VERSION 5.7 ;
  NOWIREEXTENSIONATPIN ON ;
  DIVIDERCHAR "/" ;
  BUSBITCHARS "[]" ;
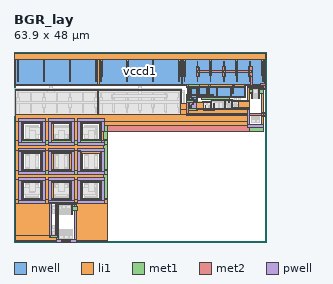
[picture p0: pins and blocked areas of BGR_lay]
MACRO BGR_lay
  CLASS BLOCK ;
  FOREIGN BGR_lay ;
  ORIGIN 0.000 0.000 ;
  SIZE 63.900 BY 48.000 ;
  PIN vccd1
    DIRECTION INOUT ;
    USE POWER ;
    PORT
      LAYER nwell ;
        RECT 0.135 39.565 63.645 46.405 ;
        RECT 43.500 38.980 58.500 39.565 ;
        RECT 43.950 36.430 58.500 38.980 ;
        RECT 43.950 36.415 51.505 36.430 ;
        RECT 43.950 35.550 46.410 36.415 ;
      LAYER li1 ;
        RECT 0.050 46.080 63.650 47.580 ;
        RECT 0.315 46.055 63.465 46.080 ;
        RECT 0.315 39.915 0.485 46.055 ;
        RECT 0.885 40.725 1.055 45.605 ;
        RECT 7.465 40.725 7.635 45.605 ;
        RECT 14.045 40.725 14.215 45.605 ;
        RECT 20.625 40.725 20.795 45.605 ;
        RECT 21.195 39.915 21.535 46.055 ;
        RECT 21.935 40.725 22.105 45.605 ;
        RECT 28.515 40.725 28.685 45.605 ;
        RECT 35.095 40.725 35.265 45.605 ;
        RECT 41.675 40.725 41.845 45.605 ;
        RECT 42.245 39.915 42.585 46.055 ;
        RECT 42.985 40.725 43.155 45.605 ;
        RECT 49.565 40.725 49.735 45.605 ;
        RECT 56.145 40.725 56.315 45.605 ;
        RECT 62.725 40.725 62.895 45.605 ;
        RECT 63.295 39.915 63.465 46.055 ;
        RECT 0.315 39.745 63.465 39.915 ;
        RECT 43.500 39.180 58.250 39.745 ;
        RECT 44.120 39.175 58.250 39.180 ;
        RECT 44.120 39.105 58.315 39.175 ;
        RECT 44.120 39.030 46.335 39.105 ;
        RECT 44.130 35.900 44.300 39.030 ;
        RECT 44.700 36.710 44.870 38.590 ;
        RECT 46.060 36.765 46.335 39.030 ;
        RECT 46.735 37.575 46.905 38.655 ;
        RECT 48.595 36.765 48.895 39.105 ;
        RECT 51.155 39.020 58.315 39.105 ;
        RECT 49.295 37.575 49.465 38.655 ;
        RECT 51.155 36.880 51.450 39.020 ;
        RECT 54.710 39.005 58.315 39.020 ;
        RECT 54.710 36.880 54.885 39.005 ;
        RECT 55.285 37.675 55.455 38.555 ;
        RECT 51.155 36.865 54.885 36.880 ;
        RECT 58.145 36.865 58.315 39.005 ;
        RECT 51.155 36.765 58.315 36.865 ;
        RECT 46.060 36.710 58.315 36.765 ;
        RECT 46.060 36.595 51.325 36.710 ;
        RECT 54.715 36.695 58.315 36.710 ;
        RECT 46.060 35.900 46.230 36.595 ;
        RECT 44.130 35.730 46.230 35.900 ;
      LAYER met1 ;
        RECT 0.000 46.080 63.700 47.580 ;
        RECT 0.800 41.880 1.200 46.080 ;
        RECT 7.350 41.930 7.750 46.080 ;
        RECT 13.900 41.930 14.300 46.080 ;
        RECT 0.855 40.665 1.085 41.880 ;
        RECT 7.435 40.665 7.665 41.930 ;
        RECT 14.015 40.665 14.245 41.930 ;
        RECT 20.550 41.830 20.950 46.080 ;
        RECT 20.595 40.665 20.825 41.830 ;
        RECT 21.850 41.780 22.250 46.080 ;
        RECT 28.400 41.830 28.800 46.080 ;
        RECT 34.950 41.880 35.350 46.080 ;
        RECT 41.550 41.930 41.950 46.080 ;
        RECT 42.850 41.930 43.250 46.080 ;
        RECT 49.450 41.980 49.850 46.080 ;
        RECT 56.050 41.980 56.450 46.080 ;
        RECT 62.600 41.980 63.000 46.080 ;
        RECT 21.905 40.665 22.135 41.780 ;
        RECT 28.485 40.665 28.715 41.830 ;
        RECT 35.065 40.665 35.295 41.880 ;
        RECT 41.645 40.665 41.875 41.930 ;
        RECT 42.955 40.665 43.185 41.930 ;
        RECT 49.535 40.665 49.765 41.980 ;
        RECT 56.115 40.665 56.345 41.980 ;
        RECT 62.695 40.665 62.925 41.980 ;
        RECT 43.970 39.130 46.950 39.680 ;
        RECT 49.150 39.380 49.600 39.730 ;
        RECT 55.150 39.430 55.600 39.830 ;
        RECT 43.970 38.830 46.420 39.130 ;
        RECT 44.670 38.650 44.870 38.830 ;
        RECT 44.670 36.650 44.900 38.650 ;
        RECT 46.700 37.530 46.950 39.130 ;
        RECT 49.250 37.530 49.500 39.380 ;
        RECT 55.250 37.630 55.500 39.430 ;
        RECT 55.255 37.615 55.485 37.630 ;
        RECT 46.705 37.515 46.935 37.530 ;
        RECT 49.265 37.515 49.495 37.530 ;
      LAYER met2 ;
        RECT 0.050 46.030 63.650 47.630 ;
        RECT 61.350 45.980 63.400 46.030 ;
    END
    PORT
      LAYER pwell ;
        RECT 58.970 38.850 63.080 39.360 ;
        RECT 44.005 33.265 46.365 35.455 ;
        RECT 1.200 30.365 7.900 31.130 ;
        RECT 1.200 25.195 1.965 30.365 ;
        RECT 7.135 25.195 7.900 30.365 ;
        RECT 1.200 24.430 7.900 25.195 ;
        RECT 8.640 30.365 15.340 31.130 ;
        RECT 8.640 25.195 9.405 30.365 ;
        RECT 14.575 25.195 15.340 30.365 ;
        RECT 8.640 24.430 15.340 25.195 ;
        RECT 16.080 30.365 22.780 31.130 ;
        RECT 16.080 25.195 16.845 30.365 ;
        RECT 22.015 25.195 22.780 30.365 ;
        RECT 58.970 29.610 59.580 38.850 ;
        RECT 62.470 29.610 63.080 38.850 ;
        RECT 58.970 28.900 63.080 29.610 ;
        RECT 16.080 24.430 22.780 25.195 ;
        RECT 1.200 22.915 7.900 23.680 ;
        RECT 1.200 17.745 1.965 22.915 ;
        RECT 7.135 17.745 7.900 22.915 ;
        RECT 1.200 16.980 7.900 17.745 ;
        RECT 8.650 22.915 15.350 23.680 ;
        RECT 8.650 17.745 9.415 22.915 ;
        RECT 14.585 17.745 15.350 22.915 ;
        RECT 8.650 16.980 15.350 17.745 ;
        RECT 16.100 22.965 22.800 23.730 ;
        RECT 16.100 17.795 16.865 22.965 ;
        RECT 22.035 17.795 22.800 22.965 ;
        RECT 16.100 17.030 22.800 17.795 ;
        RECT 1.200 15.565 7.900 16.330 ;
        RECT 1.200 10.395 1.965 15.565 ;
        RECT 7.135 10.395 7.900 15.565 ;
        RECT 1.200 9.630 7.900 10.395 ;
        RECT 8.640 15.565 15.340 16.330 ;
        RECT 8.640 10.395 9.405 15.565 ;
        RECT 14.575 10.395 15.340 15.565 ;
        RECT 8.640 10.060 15.340 10.395 ;
        RECT 16.080 15.565 22.780 16.330 ;
        RECT 16.080 10.395 16.845 15.565 ;
        RECT 22.015 10.395 22.780 15.565 ;
        RECT 8.640 9.630 15.780 10.060 ;
        RECT 16.080 9.630 22.780 10.395 ;
        RECT 9.050 9.620 15.780 9.630 ;
        RECT 9.050 1.560 9.480 9.620 ;
        RECT 10.530 9.600 15.780 9.620 ;
        RECT 10.530 1.560 11.130 9.600 ;
        RECT 9.050 1.130 11.130 1.560 ;
        RECT 10.670 0.560 11.130 1.130 ;
        RECT 15.320 0.560 15.780 9.600 ;
        RECT 10.670 0.000 15.780 0.560 ;
      LAYER li1 ;
        RECT 59.100 38.980 62.950 39.230 ;
        RECT 0.315 38.355 42.265 38.525 ;
        RECT 0.315 32.265 0.485 38.355 ;
        RECT 21.195 32.265 21.385 38.355 ;
        RECT 42.095 35.030 42.265 38.355 ;
        RECT 53.315 35.890 55.215 35.925 ;
        RECT 49.830 35.755 55.215 35.890 ;
        RECT 49.830 35.720 53.485 35.755 ;
        RECT 49.830 35.390 50.000 35.720 ;
        RECT 47.730 35.330 50.000 35.390 ;
        RECT 46.200 35.325 50.000 35.330 ;
        RECT 44.135 35.220 50.000 35.325 ;
        RECT 44.135 35.155 47.900 35.220 ;
        RECT 44.135 35.030 44.305 35.155 ;
        RECT 42.095 33.580 44.305 35.030 ;
        RECT 44.705 34.015 44.875 34.395 ;
        RECT 46.065 33.630 47.900 35.155 ;
        RECT 48.300 34.080 48.470 34.460 ;
        RECT 49.660 33.630 50.000 35.220 ;
        RECT 50.400 34.080 50.570 34.960 ;
        RECT 53.260 33.665 53.485 35.720 ;
        RECT 55.045 35.725 55.215 35.755 ;
        RECT 59.100 35.730 59.450 38.980 ;
        RECT 61.750 36.310 62.100 38.470 ;
        RECT 56.800 35.725 59.450 35.730 ;
        RECT 55.045 35.555 59.450 35.725 ;
        RECT 55.045 33.965 55.235 35.555 ;
        RECT 56.645 33.965 59.450 35.555 ;
        RECT 55.045 33.665 59.450 33.965 ;
        RECT 53.260 33.630 59.450 33.665 ;
        RECT 46.065 33.580 59.450 33.630 ;
        RECT 42.095 32.265 59.450 33.580 ;
        RECT 0.315 32.130 59.450 32.265 ;
        RECT 0.300 30.505 59.450 32.130 ;
        RECT 0.300 25.680 1.825 30.505 ;
        RECT 2.145 29.825 6.955 30.185 ;
        RECT 2.145 25.735 2.505 29.825 ;
        RECT 6.595 25.735 6.955 29.825 ;
        RECT 2.145 25.680 6.955 25.735 ;
        RECT 7.275 25.680 9.265 30.505 ;
        RECT 9.585 29.825 14.395 30.185 ;
        RECT 9.585 25.735 9.945 29.825 ;
        RECT 14.035 25.735 14.395 29.825 ;
        RECT 9.585 25.680 14.395 25.735 ;
        RECT 14.715 25.680 16.705 30.505 ;
        RECT 17.025 29.825 21.835 30.185 ;
        RECT 17.025 25.735 17.385 29.825 ;
        RECT 21.475 25.735 21.835 29.825 ;
        RECT 17.025 25.680 21.835 25.735 ;
        RECT 22.155 29.480 59.450 30.505 ;
        RECT 62.600 29.480 62.950 38.980 ;
        RECT 22.155 27.980 62.950 29.480 ;
        RECT 22.155 25.680 23.600 27.980 ;
        RECT 0.300 23.105 23.600 25.680 ;
        RECT 0.300 23.055 16.725 23.105 ;
        RECT 0.300 18.080 1.825 23.055 ;
        RECT 2.145 22.375 6.955 22.735 ;
        RECT 2.145 18.285 2.505 22.375 ;
        RECT 6.595 18.285 6.955 22.375 ;
        RECT 2.145 18.080 6.955 18.285 ;
        RECT 7.275 18.080 9.275 23.055 ;
        RECT 9.595 22.375 14.405 22.735 ;
        RECT 9.595 18.285 9.955 22.375 ;
        RECT 14.045 18.285 14.405 22.375 ;
        RECT 9.595 18.080 14.405 18.285 ;
        RECT 14.725 18.080 16.725 23.055 ;
        RECT 17.045 22.425 21.855 22.785 ;
        RECT 17.045 18.335 17.405 22.425 ;
        RECT 21.495 18.335 21.855 22.425 ;
        RECT 17.045 18.080 21.855 18.335 ;
        RECT 22.175 18.080 23.600 23.105 ;
        RECT 0.300 15.705 23.600 18.080 ;
        RECT 0.300 10.830 1.825 15.705 ;
        RECT 2.145 15.025 6.955 15.385 ;
        RECT 2.145 10.935 2.505 15.025 ;
        RECT 6.595 10.935 6.955 15.025 ;
        RECT 2.145 10.830 6.955 10.935 ;
        RECT 7.275 10.830 9.265 15.705 ;
        RECT 9.585 15.025 14.395 15.385 ;
        RECT 9.585 10.935 9.945 15.025 ;
        RECT 14.035 10.935 14.395 15.025 ;
        RECT 9.585 10.830 14.395 10.935 ;
        RECT 14.715 10.830 16.705 15.705 ;
        RECT 17.025 15.025 21.835 15.385 ;
        RECT 17.025 10.935 17.385 15.025 ;
        RECT 21.475 10.935 21.835 15.025 ;
        RECT 17.025 10.830 21.835 10.935 ;
        RECT 22.155 10.830 23.600 15.705 ;
        RECT 0.300 9.750 23.600 10.830 ;
        RECT 0.300 1.545 9.350 9.750 ;
        RECT 10.660 9.730 23.600 9.750 ;
        RECT 10.660 1.545 11.000 9.730 ;
        RECT 14.550 7.010 14.900 9.170 ;
        RECT 0.300 0.430 11.000 1.545 ;
        RECT 15.450 0.430 23.600 9.730 ;
        RECT 0.300 0.130 23.600 0.430 ;
      LAYER met1 ;
        RECT 61.800 38.430 62.050 38.440 ;
        RECT 61.750 37.580 62.950 38.430 ;
        RECT 61.800 36.335 62.050 37.580 ;
        RECT 50.370 34.980 50.600 35.020 ;
        RECT 44.675 34.430 44.905 34.455 ;
        RECT 44.670 33.955 44.905 34.430 ;
        RECT 48.270 34.020 48.500 34.520 ;
        RECT 44.670 33.680 44.870 33.955 ;
        RECT 44.070 33.130 46.370 33.680 ;
        RECT 48.300 33.630 48.450 34.020 ;
        RECT 50.350 33.630 50.600 34.980 ;
        RECT 47.750 33.130 50.600 33.630 ;
        RECT 22.650 27.980 62.950 29.480 ;
        RECT 22.650 25.880 23.600 27.980 ;
        RECT 1.350 24.580 23.600 25.880 ;
        RECT 22.650 18.380 23.600 24.580 ;
        RECT 1.350 17.080 23.600 18.380 ;
        RECT 22.650 11.030 23.600 17.080 ;
        RECT 1.350 9.730 23.600 11.030 ;
        RECT 14.600 8.880 14.850 9.140 ;
        RECT 14.600 7.930 16.050 8.880 ;
        RECT 14.600 7.035 14.850 7.930 ;
        RECT 9.165 1.245 10.865 1.545 ;
        RECT 12.050 0.130 14.300 0.430 ;
      LAYER met2 ;
        RECT 23.600 27.930 59.450 29.530 ;
    END
    PORT
      LAYER li1 ;
        RECT 46.275 40.725 46.445 45.605 ;
        RECT 52.855 40.725 53.025 45.605 ;
        RECT 59.435 40.725 59.605 45.605 ;
        RECT 59.950 36.320 60.300 38.480 ;
      LAYER met1 ;
        RECT 46.245 44.180 46.475 45.665 ;
        RECT 52.825 44.230 53.055 45.665 ;
        RECT 59.405 44.380 59.635 45.665 ;
        RECT 46.050 41.780 46.750 44.180 ;
        RECT 52.650 41.830 53.350 44.230 ;
        RECT 59.200 41.980 59.900 44.380 ;
        RECT 46.245 40.665 46.475 41.780 ;
        RECT 52.825 40.665 53.055 41.830 ;
        RECT 59.405 40.665 59.635 41.980 ;
        RECT 59.600 37.680 60.350 38.630 ;
        RECT 60.000 36.345 60.250 37.680 ;
      LAYER met2 ;
        RECT 46.100 43.330 46.700 44.230 ;
        RECT 52.700 43.330 53.300 44.280 ;
        RECT 59.250 43.330 60.300 44.430 ;
        RECT 46.100 42.730 60.300 43.330 ;
        RECT 46.100 41.730 46.700 42.730 ;
        RECT 52.700 41.780 53.300 42.730 ;
        RECT 59.250 41.930 60.300 42.730 ;
        RECT 59.650 39.630 60.300 41.930 ;
        RECT 62.150 39.630 63.650 39.980 ;
        RECT 59.650 38.780 63.650 39.630 ;
        RECT 59.650 37.630 60.300 38.780 ;
        RECT 62.150 38.480 63.650 38.780 ;
    END
    PORT
      LAYER li1 ;
        RECT 47.045 37.110 47.885 37.280 ;
        RECT 49.605 37.110 50.445 37.280 ;
        RECT 45.010 36.245 45.350 36.415 ;
        RECT 54.100 35.245 54.430 35.415 ;
        RECT 45.015 34.645 45.355 34.815 ;
      LAYER met1 ;
        RECT 46.900 36.980 48.000 37.330 ;
        RECT 49.500 37.310 50.350 37.330 ;
        RECT 49.500 37.080 50.505 37.310 ;
        RECT 49.500 37.030 50.350 37.080 ;
        RECT 44.950 36.215 45.410 36.445 ;
        RECT 47.300 36.380 47.550 36.980 ;
        RECT 45.020 35.630 45.370 36.215 ;
        RECT 47.300 36.080 54.450 36.380 ;
        RECT 43.550 35.230 45.370 35.630 ;
        RECT 54.100 35.230 54.450 36.080 ;
        RECT 45.020 34.845 45.370 35.230 ;
        RECT 54.120 35.215 54.410 35.230 ;
        RECT 44.955 34.615 45.415 34.845 ;
      LAYER met2 ;
        RECT 46.950 37.330 47.950 37.380 ;
        RECT 49.550 37.330 50.300 37.380 ;
        RECT 43.600 37.130 50.300 37.330 ;
        RECT 43.600 35.680 43.950 37.130 ;
        RECT 46.950 36.930 47.950 37.130 ;
        RECT 49.550 36.980 50.300 37.130 ;
        RECT 43.600 32.430 44.000 35.680 ;
        RECT 62.600 32.430 63.600 32.780 ;
        RECT 43.600 32.030 63.600 32.430 ;
        RECT 62.600 31.780 63.600 32.030 ;
    END
  END vccd1
  OBS
      LAYER pwell ;
        RECT 0.185 31.965 42.395 38.655 ;
        RECT 53.185 36.020 55.345 36.055 ;
        RECT 49.700 35.855 55.345 36.020 ;
        RECT 49.700 35.520 56.945 35.855 ;
        RECT 47.600 33.665 56.945 35.520 ;
        RECT 47.600 33.365 55.345 33.665 ;
        RECT 47.600 33.330 53.560 33.365 ;
        RECT 49.720 33.000 50.730 33.330 ;
      LAYER li1 ;
        RECT 4.175 40.725 4.345 45.605 ;
        RECT 10.755 40.725 10.925 45.605 ;
        RECT 17.335 40.725 17.505 45.605 ;
        RECT 25.225 40.725 25.395 45.605 ;
        RECT 31.805 40.725 31.975 45.605 ;
        RECT 38.385 40.725 38.555 45.605 ;
        RECT 1.195 40.260 4.035 40.430 ;
        RECT 4.485 40.260 7.325 40.430 ;
        RECT 7.775 40.260 10.615 40.430 ;
        RECT 11.065 40.260 13.905 40.430 ;
        RECT 14.355 40.260 17.195 40.430 ;
        RECT 17.645 40.260 20.485 40.430 ;
        RECT 22.245 40.260 25.085 40.430 ;
        RECT 25.535 40.260 28.375 40.430 ;
        RECT 28.825 40.260 31.665 40.430 ;
        RECT 32.115 40.260 34.955 40.430 ;
        RECT 35.405 40.260 38.245 40.430 ;
        RECT 38.695 40.260 41.535 40.430 ;
        RECT 43.295 40.260 46.135 40.430 ;
        RECT 46.585 40.260 49.425 40.430 ;
        RECT 49.875 40.260 52.715 40.430 ;
        RECT 53.165 40.260 56.005 40.430 ;
        RECT 56.455 40.260 59.295 40.430 ;
        RECT 59.745 40.260 62.585 40.430 ;
        RECT 1.195 37.845 4.035 38.015 ;
        RECT 4.485 37.845 7.325 38.015 ;
        RECT 7.775 37.845 10.615 38.015 ;
        RECT 11.065 37.845 13.905 38.015 ;
        RECT 14.355 37.845 17.195 38.015 ;
        RECT 17.645 37.845 20.485 38.015 ;
        RECT 22.095 37.845 24.935 38.015 ;
        RECT 25.385 37.845 28.225 38.015 ;
        RECT 28.675 37.845 31.515 38.015 ;
        RECT 31.965 37.845 34.805 38.015 ;
        RECT 35.255 37.845 38.095 38.015 ;
        RECT 38.545 37.845 41.385 38.015 ;
        RECT 0.885 32.715 1.055 37.595 ;
        RECT 4.175 32.715 4.345 37.595 ;
        RECT 7.465 32.715 7.635 37.595 ;
        RECT 10.755 32.715 10.925 37.595 ;
        RECT 14.045 32.715 14.215 37.595 ;
        RECT 17.335 32.715 17.505 37.595 ;
        RECT 20.625 32.715 20.795 37.595 ;
        RECT 21.785 32.715 21.955 37.595 ;
        RECT 25.075 32.715 25.245 37.595 ;
        RECT 28.365 32.715 28.535 37.595 ;
        RECT 31.655 32.715 31.825 37.595 ;
        RECT 34.945 32.715 35.115 37.595 ;
        RECT 38.235 32.715 38.405 37.595 ;
        RECT 41.525 32.715 41.695 37.595 ;
        RECT 45.490 36.710 45.660 38.590 ;
        RECT 48.025 37.575 48.195 38.655 ;
        RECT 50.585 37.575 50.755 38.655 ;
        RECT 51.850 37.690 52.020 38.570 ;
        RECT 54.140 37.690 54.310 38.570 ;
        RECT 57.575 37.675 57.745 38.555 ;
        RECT 52.160 37.225 54.000 37.395 ;
        RECT 55.595 37.210 57.435 37.380 ;
        RECT 60.550 36.310 60.900 38.470 ;
        RECT 61.150 36.310 61.500 38.470 ;
        RECT 50.710 35.210 52.550 35.380 ;
        RECT 55.775 35.045 56.105 35.215 ;
        RECT 48.610 34.710 48.950 34.880 ;
        RECT 45.495 34.015 45.665 34.395 ;
        RECT 49.090 34.080 49.260 34.460 ;
        RECT 52.690 34.080 52.860 34.960 ;
        RECT 53.885 34.115 54.055 34.995 ;
        RECT 54.475 34.115 54.645 34.995 ;
        RECT 55.635 34.415 55.805 34.795 ;
        RECT 56.075 34.415 56.245 34.795 ;
        RECT 59.950 30.140 60.300 32.300 ;
        RECT 60.550 30.130 60.900 32.290 ;
        RECT 61.150 30.130 61.500 32.290 ;
        RECT 61.750 30.130 62.100 32.290 ;
        RECT 2.815 26.045 6.285 29.515 ;
        RECT 10.255 26.045 13.725 29.515 ;
        RECT 17.695 26.045 21.165 29.515 ;
        RECT 2.815 18.595 6.285 22.065 ;
        RECT 10.265 18.595 13.735 22.065 ;
        RECT 17.715 18.645 21.185 22.115 ;
        RECT 2.815 11.245 6.285 14.715 ;
        RECT 10.255 11.245 13.725 14.715 ;
        RECT 17.695 11.245 21.165 14.715 ;
        RECT 9.830 7.110 10.180 9.270 ;
        RECT 11.550 7.010 11.900 9.170 ;
        RECT 12.150 7.010 12.500 9.170 ;
        RECT 12.750 7.010 13.100 9.170 ;
        RECT 13.350 7.010 13.700 9.170 ;
        RECT 13.950 7.010 14.300 9.170 ;
        RECT 9.830 1.910 10.180 4.070 ;
        RECT 11.550 0.930 11.900 3.090 ;
        RECT 12.150 0.930 12.500 3.090 ;
        RECT 12.750 0.930 13.100 3.090 ;
        RECT 13.350 0.930 13.700 3.090 ;
        RECT 13.950 0.930 14.300 3.090 ;
        RECT 14.550 0.930 14.900 3.090 ;
      LAYER met1 ;
        RECT 4.145 44.530 4.375 45.665 ;
        RECT 3.950 42.130 4.550 44.530 ;
        RECT 10.725 44.480 10.955 45.665 ;
        RECT 4.145 40.665 4.375 42.130 ;
        RECT 10.550 42.080 11.250 44.480 ;
        RECT 17.305 44.430 17.535 45.665 ;
        RECT 10.725 40.665 10.955 42.080 ;
        RECT 17.150 42.030 17.850 44.430 ;
        RECT 25.195 44.330 25.425 45.665 ;
        RECT 17.305 40.665 17.535 42.030 ;
        RECT 25.000 41.930 25.700 44.330 ;
        RECT 31.775 44.230 32.005 45.665 ;
        RECT 25.195 40.665 25.425 41.930 ;
        RECT 31.550 40.460 32.250 44.230 ;
        RECT 38.355 44.180 38.585 45.665 ;
        RECT 38.200 41.780 38.900 44.180 ;
        RECT 38.355 40.665 38.585 41.780 ;
        RECT 1.135 40.430 4.095 40.460 ;
        RECT 4.425 40.430 7.385 40.460 ;
        RECT 7.715 40.430 10.675 40.460 ;
        RECT 11.005 40.430 13.965 40.460 ;
        RECT 14.295 40.430 17.255 40.460 ;
        RECT 17.585 40.430 20.545 40.460 ;
        RECT 1.135 40.410 20.545 40.430 ;
        RECT 22.135 40.430 25.145 40.460 ;
        RECT 25.425 40.430 28.435 40.460 ;
        RECT 28.715 40.430 35.015 40.460 ;
        RECT 35.295 40.430 38.305 40.460 ;
        RECT 38.585 40.430 41.595 40.460 ;
        RECT 22.135 40.410 41.595 40.430 ;
        RECT 43.235 40.410 46.195 40.460 ;
        RECT 46.525 40.410 49.485 40.460 ;
        RECT 49.815 40.410 52.775 40.460 ;
        RECT 53.105 40.410 56.065 40.460 ;
        RECT 56.395 40.410 59.355 40.460 ;
        RECT 59.685 40.410 62.645 40.460 ;
        RECT 1.135 40.380 46.195 40.410 ;
        RECT 46.450 40.380 49.485 40.410 ;
        RECT 49.740 40.380 52.775 40.410 ;
        RECT 53.030 40.380 56.065 40.410 ;
        RECT 56.320 40.380 59.355 40.410 ;
        RECT 59.610 40.380 62.645 40.410 ;
        RECT 1.135 40.230 62.645 40.380 ;
        RECT 1.200 40.180 62.620 40.230 ;
        RECT 1.200 40.030 62.525 40.180 ;
        RECT 43.225 39.980 62.525 40.030 ;
        RECT 50.550 39.730 50.800 39.980 ;
        RECT 50.500 39.280 50.900 39.730 ;
        RECT 1.100 37.830 43.100 38.230 ;
        RECT 1.135 37.815 7.385 37.830 ;
        RECT 7.715 37.815 13.965 37.830 ;
        RECT 14.295 37.815 41.445 37.830 ;
        RECT 0.855 36.530 1.085 37.655 ;
        RECT 0.650 34.130 1.350 36.530 ;
        RECT 0.855 32.655 1.085 34.130 ;
        RECT 4.050 33.980 4.450 37.815 ;
        RECT 7.435 36.430 7.665 37.655 ;
        RECT 7.200 34.030 7.900 36.430 ;
        RECT 4.145 32.655 4.375 33.980 ;
        RECT 7.435 32.655 7.665 34.030 ;
        RECT 10.650 33.930 11.050 37.815 ;
        RECT 14.015 36.380 14.245 37.655 ;
        RECT 13.750 33.980 14.450 36.380 ;
        RECT 10.725 32.655 10.955 33.930 ;
        RECT 14.015 32.655 14.245 33.980 ;
        RECT 17.200 33.930 17.600 37.815 ;
        RECT 20.595 36.430 20.825 37.655 ;
        RECT 21.755 36.430 21.985 37.655 ;
        RECT 25.045 37.280 25.275 37.655 ;
        RECT 20.350 34.030 21.050 36.430 ;
        RECT 21.650 34.030 22.350 36.430 ;
        RECT 24.750 36.280 25.500 37.280 ;
        RECT 28.335 36.330 28.565 37.655 ;
        RECT 31.625 37.430 31.855 37.655 ;
        RECT 31.400 36.430 32.150 37.430 ;
        RECT 17.305 32.655 17.535 33.930 ;
        RECT 20.595 32.655 20.825 34.030 ;
        RECT 21.755 32.655 21.985 34.030 ;
        RECT 24.800 32.980 25.450 36.280 ;
        RECT 28.100 33.930 28.800 36.330 ;
        RECT 25.045 32.655 25.275 32.980 ;
        RECT 28.335 32.655 28.565 33.930 ;
        RECT 31.450 33.130 32.100 36.430 ;
        RECT 34.915 36.330 35.145 37.655 ;
        RECT 38.205 37.380 38.435 37.655 ;
        RECT 37.950 36.380 38.700 37.380 ;
        RECT 34.700 33.930 35.400 36.330 ;
        RECT 31.625 32.655 31.855 33.130 ;
        RECT 34.915 32.655 35.145 33.930 ;
        RECT 38.000 33.080 38.650 36.380 ;
        RECT 41.495 36.330 41.725 37.655 ;
        RECT 41.250 33.930 41.950 36.330 ;
        RECT 38.205 32.655 38.435 33.080 ;
        RECT 41.495 32.655 41.725 33.930 ;
        RECT 42.700 32.880 43.100 37.830 ;
        RECT 45.460 37.330 45.690 38.650 ;
        RECT 47.995 38.230 48.225 38.715 ;
        RECT 47.995 37.980 48.750 38.230 ;
        RECT 47.995 37.515 48.225 37.980 ;
        RECT 45.460 36.980 46.370 37.330 ;
        RECT 45.460 36.650 45.690 36.980 ;
        RECT 45.970 35.580 46.370 36.980 ;
        RECT 48.550 36.880 48.750 37.980 ;
        RECT 50.550 37.530 50.800 39.280 ;
        RECT 51.820 38.380 52.050 38.630 ;
        RECT 51.300 37.880 52.050 38.380 ;
        RECT 50.555 37.515 50.785 37.530 ;
        RECT 51.300 36.980 51.550 37.880 ;
        RECT 51.820 37.630 52.050 37.880 ;
        RECT 54.110 38.580 54.340 38.630 ;
        RECT 57.500 38.615 57.750 38.630 ;
        RECT 54.110 37.630 54.350 38.580 ;
        RECT 54.150 37.430 54.350 37.630 ;
        RECT 57.500 37.615 57.775 38.615 ;
        RECT 60.550 37.630 61.500 38.480 ;
        RECT 57.500 37.430 57.750 37.615 ;
        RECT 52.600 37.425 53.200 37.430 ;
        RECT 53.500 37.425 54.350 37.430 ;
        RECT 52.100 37.230 54.350 37.425 ;
        RECT 57.400 37.410 57.750 37.430 ;
        RECT 55.535 37.380 57.750 37.410 ;
        RECT 55.500 37.230 57.750 37.380 ;
        RECT 52.100 37.195 54.060 37.230 ;
        RECT 52.600 37.130 53.200 37.195 ;
        RECT 55.500 37.180 57.495 37.230 ;
        RECT 55.750 36.980 56.100 37.180 ;
        RECT 51.300 36.880 56.100 36.980 ;
        RECT 48.550 36.680 56.100 36.880 ;
        RECT 49.550 35.580 51.050 35.880 ;
        RECT 45.600 35.180 49.000 35.580 ;
        RECT 45.465 34.380 45.695 34.455 ;
        RECT 45.970 34.380 46.370 35.180 ;
        RECT 48.550 34.910 49.000 35.180 ;
        RECT 48.550 34.680 49.010 34.910 ;
        RECT 45.465 34.030 46.370 34.380 ;
        RECT 49.060 34.430 49.290 34.520 ;
        RECT 49.550 34.430 49.850 35.580 ;
        RECT 50.700 35.410 51.050 35.580 ;
        RECT 52.400 35.410 53.600 35.430 ;
        RECT 50.650 35.180 53.600 35.410 ;
        RECT 49.060 34.130 49.850 34.430 ;
        RECT 45.465 33.955 45.695 34.030 ;
        RECT 49.060 34.020 49.290 34.130 ;
        RECT 51.600 32.880 51.900 35.180 ;
        RECT 52.660 34.930 52.890 35.020 ;
        RECT 52.650 34.880 52.890 34.930 ;
        RECT 53.400 34.880 53.600 35.180 ;
        RECT 53.855 34.880 54.085 35.055 ;
        RECT 52.600 34.130 53.050 34.880 ;
        RECT 53.400 34.680 54.085 34.880 ;
        RECT 52.660 34.020 52.890 34.130 ;
        RECT 53.855 34.055 54.085 34.680 ;
        RECT 54.445 34.830 54.675 35.055 ;
        RECT 55.750 35.030 56.100 36.680 ;
        RECT 60.600 36.335 60.850 37.630 ;
        RECT 61.200 36.335 61.450 37.630 ;
        RECT 55.795 35.015 56.085 35.030 ;
        RECT 55.605 34.830 55.835 34.855 ;
        RECT 54.445 34.380 55.835 34.830 ;
        RECT 54.445 34.055 54.675 34.380 ;
        RECT 55.605 34.355 55.835 34.380 ;
        RECT 56.045 34.780 56.275 34.855 ;
        RECT 56.750 34.780 57.300 34.830 ;
        RECT 56.045 34.430 57.300 34.780 ;
        RECT 56.045 34.355 56.275 34.430 ;
        RECT 42.700 32.480 51.900 32.880 ;
        RECT 60.000 30.980 60.250 32.275 ;
        RECT 60.600 30.980 60.850 32.265 ;
        RECT 61.200 30.980 61.450 32.265 ;
        RECT 61.800 30.980 62.050 32.265 ;
        RECT 59.950 30.130 60.900 30.980 ;
        RECT 61.150 30.130 62.100 30.980 ;
        RECT 3.025 26.255 6.075 29.305 ;
        RECT 10.465 26.255 13.515 29.305 ;
        RECT 17.905 26.255 20.955 29.305 ;
        RECT 10.500 21.855 13.500 21.880 ;
        RECT 3.025 18.805 6.075 21.855 ;
        RECT 10.475 18.805 13.525 21.855 ;
        RECT 17.925 18.855 20.975 21.905 ;
        RECT 10.500 18.730 13.500 18.805 ;
        RECT 0.300 3.330 0.950 13.880 ;
        RECT 3.025 11.455 6.075 14.505 ;
        RECT 10.465 11.455 13.515 14.505 ;
        RECT 17.905 11.455 20.955 14.505 ;
        RECT 9.815 8.880 10.165 9.295 ;
        RECT 11.600 8.880 11.850 9.140 ;
        RECT 9.815 8.130 11.900 8.880 ;
        RECT 12.150 8.430 13.100 9.180 ;
        RECT 13.350 8.430 14.300 9.180 ;
        RECT 9.815 7.145 10.165 8.130 ;
        RECT 9.880 7.135 10.130 7.145 ;
        RECT 11.600 7.035 11.850 8.130 ;
        RECT 12.200 7.035 12.450 8.430 ;
        RECT 12.800 7.035 13.050 8.430 ;
        RECT 13.400 7.035 13.650 8.430 ;
        RECT 14.000 7.035 14.250 8.430 ;
        RECT 9.815 3.330 10.165 4.045 ;
        RECT 0.300 2.630 10.165 3.330 ;
        RECT 9.815 1.895 10.165 2.630 ;
        RECT 11.600 1.680 11.850 3.065 ;
        RECT 12.200 1.680 12.450 3.065 ;
        RECT 12.800 1.680 13.050 3.065 ;
        RECT 13.400 1.680 13.650 3.065 ;
        RECT 14.000 1.680 14.250 3.065 ;
        RECT 14.600 1.680 14.850 3.065 ;
        RECT 11.550 0.930 12.500 1.680 ;
        RECT 12.750 0.930 13.700 1.680 ;
        RECT 13.950 0.930 14.900 1.680 ;
      LAYER met2 ;
        RECT 4.000 43.330 4.500 44.580 ;
        RECT 10.600 43.330 11.200 44.530 ;
        RECT 17.200 43.330 17.800 44.480 ;
        RECT 25.050 43.430 25.650 44.380 ;
        RECT 31.600 43.430 32.200 44.280 ;
        RECT 25.050 43.380 32.200 43.430 ;
        RECT 38.250 43.380 38.850 44.230 ;
        RECT 3.950 42.730 17.850 43.330 ;
        RECT 25.050 42.830 38.850 43.380 ;
        RECT 4.000 42.080 4.500 42.730 ;
        RECT 8.950 38.280 9.650 42.730 ;
        RECT 10.500 42.080 11.300 42.730 ;
        RECT 17.200 41.980 17.800 42.730 ;
        RECT 25.050 41.880 25.650 42.830 ;
        RECT 31.450 42.780 38.850 42.830 ;
        RECT 8.550 37.780 10.150 38.280 ;
        RECT 31.450 37.330 32.300 42.780 ;
        RECT 38.250 41.730 38.850 42.780 ;
        RECT 50.550 39.680 50.850 39.780 ;
        RECT 50.550 39.280 57.250 39.680 ;
        RECT 50.550 39.230 50.850 39.280 ;
        RECT 38.000 37.330 38.650 37.430 ;
        RECT 24.800 36.630 38.650 37.330 ;
        RECT 52.650 37.080 53.150 37.480 ;
        RECT 0.650 35.580 1.350 36.630 ;
        RECT 7.250 35.580 7.850 36.480 ;
        RECT 13.800 35.580 14.400 36.430 ;
        RECT 20.400 35.580 21.000 36.480 ;
        RECT 0.650 34.980 21.000 35.580 ;
        RECT 0.650 24.280 1.350 34.980 ;
        RECT 7.250 33.980 7.850 34.980 ;
        RECT 13.800 33.930 14.400 34.980 ;
        RECT 20.400 33.980 21.000 34.980 ;
        RECT 21.700 35.680 22.400 36.530 ;
        RECT 24.800 36.230 25.450 36.630 ;
        RECT 31.450 36.380 32.100 36.630 ;
        RECT 28.150 35.680 28.750 36.380 ;
        RECT 34.750 35.680 35.350 36.380 ;
        RECT 38.000 36.330 38.650 36.630 ;
        RECT 41.300 35.680 41.900 36.380 ;
        RECT 21.700 35.080 41.900 35.680 ;
        RECT 3.800 27.130 20.500 28.930 ;
        RECT 0.650 23.580 12.350 24.280 ;
        RECT 11.650 20.680 12.350 23.580 ;
        RECT 3.950 20.030 5.250 20.680 ;
        RECT 11.400 20.030 12.650 20.680 ;
        RECT 18.850 20.080 20.150 20.730 ;
        RECT 0.300 12.080 20.500 13.880 ;
        RECT 21.700 9.930 22.400 35.080 ;
        RECT 28.150 33.880 28.750 35.080 ;
        RECT 34.750 33.880 35.350 35.080 ;
        RECT 41.300 33.880 41.900 35.080 ;
        RECT 52.700 34.930 53.000 37.080 ;
        RECT 52.650 34.080 53.000 34.930 ;
        RECT 56.800 34.380 57.250 39.280 ;
        RECT 10.700 9.230 22.400 9.930 ;
        RECT 10.700 8.180 11.500 9.230 ;
      LAYER met3 ;
        RECT 3.850 12.730 5.350 28.230 ;
        RECT 11.300 12.730 12.800 28.230 ;
        RECT 3.900 12.605 5.250 12.730 ;
        RECT 11.350 12.705 12.750 12.730 ;
        RECT 18.800 12.680 20.300 28.180 ;
  END
END BGR_lay
END LIBRARY

